# Confidential Information of ARM, Inc.
# Use subject to ARM license.
# Copyright (c) 2026 ARM, Inc.

# ACI Version r0p0-00eac0

# Reifier 3.1.1

VERSION 5.6 ;

BUSBITCHARS "[]" ;

#name: sram_sp_hdc_svt_rvt_hvt Compiler|TSMC cln65gplus 65nm Process, 0.525um2 Bitcell
#version: r0p0-00eac0
#comment: 
#configuration:  -instname "pingpong_sram_4096x16" -words 4096 -bits 16 -frequency 100 -mux 16 -pipeline off -write_mask off -wp_size 8 -write_thru on -top_layer "m5-m9" -power_type otc -redundancy off -rcols 2 -rrows 2 -bmux off -ser none -back_biasing off -power_gating off -retention on -ema on -atf off -cust_comment "" -bus_notation on -left_bus_delim "[" -right_bus_delim "]" -pwr_gnd_rename "VDDPE:VDDPE,VDDCE:VDDCE,VSSE:VSSE" -prefix "" -name_case upper -check_instname off -diodes on -drive 6 -dnw off -asvm on -corners ff_1p10v_1p10v_125c,tt_1p00v_1p00v_25c,ff_1p10v_1p10v_0c,ss_0p90v_0p90v_125c,ff_1p10v_1p10v_m40c,ss_0p90v_0p90v_m40c
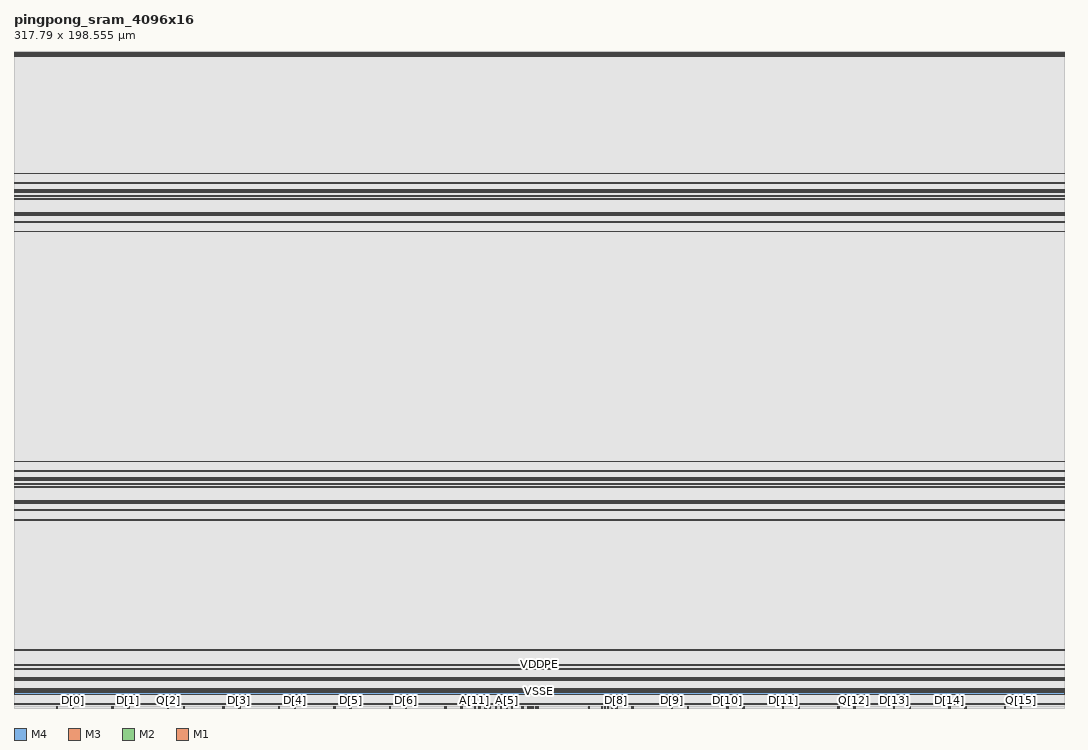
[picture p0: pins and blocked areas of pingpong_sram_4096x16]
MACRO pingpong_sram_4096x16
  FOREIGN pingpong_sram_4096x16 0 0 ;
  SYMMETRY X Y R90 ;
  SIZE 317.79 BY 198.555 ;
  CLASS BLOCK ;
  PIN A[2]
    DIRECTION INPUT ;
    USE SIGNAL ;
    SHAPE ABUTMENT ;
    PORT
      LAYER M4 ;
      RECT 155.545 0.0 155.885 0.34 ;
      LAYER M3 ;
      RECT 155.545 0.0 155.885 0.2 ;
      LAYER M2 ;
      RECT 155.545 0.0 155.885 0.2 ;
      LAYER M1 ;
      RECT 155.545 0.0 155.885 0.2 ;
      END
    ANTENNAGATEAREA 0.009 ;
    ANTENNADIFFAREA 0.1024 ;
    END A[2]
  PIN A[1]
    DIRECTION INPUT ;
    USE SIGNAL ;
    SHAPE ABUTMENT ;
    PORT
      LAYER M1 ;
      RECT 156.27 0.0 156.61 0.2 ;
      LAYER M2 ;
      RECT 156.27 0.0 156.61 0.2 ;
      LAYER M3 ;
      RECT 156.27 0.0 156.61 0.2 ;
      LAYER M4 ;
      RECT 156.27 0.0 156.61 0.34 ;
      END
    ANTENNAGATEAREA 0.009 ;
    ANTENNADIFFAREA 0.1024 ;
    END A[1]
  PIN A[3]
    DIRECTION INPUT ;
    USE SIGNAL ;
    SHAPE ABUTMENT ;
    PORT
      LAYER M4 ;
      RECT 153.72 0.0 154.06 0.34 ;
      LAYER M3 ;
      RECT 153.72 0.0 154.06 0.2 ;
      LAYER M2 ;
      RECT 153.72 0.0 154.06 0.2 ;
      LAYER M1 ;
      RECT 153.72 0.0 154.06 0.2 ;
      END
    ANTENNAGATEAREA 0.009 ;
    ANTENNADIFFAREA 0.1024 ;
    END A[3]
  PIN A[0]
    DIRECTION INPUT ;
    USE SIGNAL ;
    SHAPE ABUTMENT ;
    PORT
      LAYER M1 ;
      RECT 156.945 0.0 157.285 0.2 ;
      LAYER M2 ;
      RECT 156.945 0.0 157.285 0.2 ;
      LAYER M3 ;
      RECT 156.945 0.0 157.285 0.2 ;
      LAYER M4 ;
      RECT 156.945 0.0 157.285 0.34 ;
      END
    ANTENNAGATEAREA 0.009 ;
    ANTENNADIFFAREA 0.1024 ;
    END A[0]
  PIN A[4]
    DIRECTION INPUT ;
    USE SIGNAL ;
    SHAPE ABUTMENT ;
    PORT
      LAYER M4 ;
      RECT 150.47 0.0 150.81 0.34 ;
      LAYER M3 ;
      RECT 150.47 0.0 150.81 0.2 ;
      LAYER M2 ;
      RECT 150.47 0.0 150.81 0.2 ;
      LAYER M1 ;
      RECT 150.47 0.0 150.81 0.2 ;
      END
    ANTENNAGATEAREA 0.009 ;
    ANTENNADIFFAREA 0.1024 ;
    END A[4]
  PIN EMA[0]
    DIRECTION INPUT ;
    USE SIGNAL ;
    SHAPE ABUTMENT ;
    PORT
      LAYER M1 ;
      RECT 157.765 0.0 158.105 0.2 ;
      LAYER M2 ;
      RECT 157.765 0.0 158.105 0.2 ;
      LAYER M3 ;
      RECT 157.765 0.0 158.105 0.2 ;
      LAYER M4 ;
      RECT 157.765 0.0 158.105 0.34 ;
      END
    ANTENNAGATEAREA 0.009 ;
    ANTENNADIFFAREA 0.1024 ;
    END EMA[0]
  PIN A[5]
    DIRECTION INPUT ;
    USE SIGNAL ;
    SHAPE ABUTMENT ;
    PORT
      LAYER M4 ;
      RECT 149.05 0.0 149.39 0.34 ;
      LAYER M3 ;
      RECT 149.05 0.0 149.39 0.2 ;
      LAYER M2 ;
      RECT 149.05 0.0 149.39 0.2 ;
      LAYER M1 ;
      RECT 149.05 0.0 149.39 0.2 ;
      END
    ANTENNAGATEAREA 0.009 ;
    ANTENNADIFFAREA 0.1024 ;
    END A[5]
  PIN EMA[1]
    DIRECTION INPUT ;
    USE SIGNAL ;
    SHAPE ABUTMENT ;
    PORT
      LAYER M1 ;
      RECT 158.345 0.0 158.685 0.2 ;
      LAYER M2 ;
      RECT 158.345 0.0 158.685 0.2 ;
      LAYER M3 ;
      RECT 158.345 0.0 158.685 0.2 ;
      LAYER M4 ;
      RECT 158.345 0.0 158.685 0.34 ;
      END
    ANTENNAGATEAREA 0.009 ;
    ANTENNADIFFAREA 0.1024 ;
    END EMA[1]
  PIN A[6]
    DIRECTION INPUT ;
    USE SIGNAL ;
    SHAPE ABUTMENT ;
    PORT
      LAYER M4 ;
      RECT 147.22 0.0 147.56 0.34 ;
      LAYER M3 ;
      RECT 147.22 0.0 147.56 0.2 ;
      LAYER M2 ;
      RECT 147.22 0.0 147.56 0.2 ;
      LAYER M1 ;
      RECT 147.22 0.0 147.56 0.2 ;
      END
    ANTENNAGATEAREA 0.009 ;
    ANTENNADIFFAREA 0.1024 ;
    END A[6]
  PIN WEN
    DIRECTION INPUT ;
    USE SIGNAL ;
    SHAPE ABUTMENT ;
    PORT
      LAYER M1 ;
      RECT 173.735 0.0 174.075 0.2 ;
      LAYER M2 ;
      RECT 173.735 0.0 174.075 0.2 ;
      LAYER M3 ;
      RECT 173.735 0.0 174.075 0.2 ;
      LAYER M4 ;
      RECT 173.735 0.0 174.075 0.34 ;
      END
    ANTENNAGATEAREA 0.009 ;
    ANTENNADIFFAREA 0.1024 ;
    END WEN
  PIN A[7]
    DIRECTION INPUT ;
    USE SIGNAL ;
    SHAPE ABUTMENT ;
    PORT
      LAYER M4 ;
      RECT 145.8 0.0 146.14 0.34 ;
      LAYER M3 ;
      RECT 145.8 0.0 146.14 0.2 ;
      LAYER M2 ;
      RECT 145.8 0.0 146.14 0.2 ;
      LAYER M1 ;
      RECT 145.8 0.0 146.14 0.2 ;
      END
    ANTENNAGATEAREA 0.009 ;
    ANTENNADIFFAREA 0.1024 ;
    END A[7]
  PIN CEN
    DIRECTION INPUT ;
    USE SIGNAL ;
    SHAPE ABUTMENT ;
    PORT
      LAYER M1 ;
      RECT 177.82 0.0 178.16 0.2 ;
      LAYER M2 ;
      RECT 177.82 0.0 178.16 0.2 ;
      LAYER M3 ;
      RECT 177.82 0.0 178.16 0.2 ;
      LAYER M4 ;
      RECT 177.82 0.0 178.16 0.34 ;
      END
    ANTENNAGATEAREA 0.009 ;
    ANTENNADIFFAREA 0.1024 ;
    END CEN
  PIN A[8]
    DIRECTION INPUT ;
    USE SIGNAL ;
    SHAPE ABUTMENT ;
    PORT
      LAYER M4 ;
      RECT 143.97 0.0 144.31 0.34 ;
      LAYER M3 ;
      RECT 143.97 0.0 144.31 0.2 ;
      LAYER M2 ;
      RECT 143.97 0.0 144.31 0.2 ;
      LAYER M1 ;
      RECT 143.97 0.0 144.31 0.2 ;
      END
    ANTENNAGATEAREA 0.009 ;
    ANTENNADIFFAREA 0.1024 ;
    END A[8]
  PIN RETN
    DIRECTION INPUT ;
    USE SIGNAL ;
    SHAPE ABUTMENT ;
    PORT
      LAYER M1 ;
      RECT 178.625 0.0 178.965 0.2 ;
      LAYER M2 ;
      RECT 178.625 0.0 178.965 0.2 ;
      LAYER M3 ;
      RECT 178.625 0.0 178.965 0.2 ;
      LAYER M4 ;
      RECT 178.625 0.0 178.965 0.34 ;
      END
    ANTENNAGATEAREA 0.009 ;
    ANTENNADIFFAREA 0.1024 ;
    END RETN
  PIN A[9]
    DIRECTION INPUT ;
    USE SIGNAL ;
    SHAPE ABUTMENT ;
    PORT
      LAYER M4 ;
      RECT 142.55 0.0 142.89 0.34 ;
      LAYER M3 ;
      RECT 142.55 0.0 142.89 0.2 ;
      LAYER M2 ;
      RECT 142.55 0.0 142.89 0.2 ;
      LAYER M1 ;
      RECT 142.55 0.0 142.89 0.2 ;
      END
    ANTENNAGATEAREA 0.009 ;
    ANTENNADIFFAREA 0.1024 ;
    END A[9]
  PIN EMA[2]
    DIRECTION INPUT ;
    USE SIGNAL ;
    SHAPE ABUTMENT ;
    PORT
      LAYER M1 ;
      RECT 179.68 0.0 180.02 0.2 ;
      LAYER M2 ;
      RECT 179.68 0.0 180.02 0.2 ;
      LAYER M3 ;
      RECT 179.68 0.0 180.02 0.2 ;
      LAYER M4 ;
      RECT 179.68 0.0 180.02 0.34 ;
      END
    ANTENNAGATEAREA 0.009 ;
    ANTENNADIFFAREA 0.1024 ;
    END EMA[2]
  PIN A[10]
    DIRECTION INPUT ;
    USE SIGNAL ;
    SHAPE ABUTMENT ;
    PORT
      LAYER M4 ;
      RECT 140.72 0.0 141.06 0.34 ;
      LAYER M3 ;
      RECT 140.72 0.0 141.06 0.2 ;
      LAYER M2 ;
      RECT 140.72 0.0 141.06 0.2 ;
      LAYER M1 ;
      RECT 140.72 0.0 141.06 0.2 ;
      END
    ANTENNAGATEAREA 0.009 ;
    ANTENNADIFFAREA 0.1024 ;
    END A[10]
  PIN CLK
    DIRECTION INPUT ;
    USE SIGNAL ;
    SHAPE ABUTMENT ;
    PORT
      LAYER M1 ;
      RECT 180.69 0.0 181.03 0.2 ;
      LAYER M2 ;
      RECT 180.69 0.0 181.03 0.2 ;
      LAYER M3 ;
      RECT 180.69 0.0 181.03 0.2 ;
      LAYER M4 ;
      RECT 180.69 0.0 181.03 0.34 ;
      END
    ANTENNAGATEAREA 0.009 ;
    ANTENNADIFFAREA 0.1024 ;
    END CLK
  PIN A[11]
    DIRECTION INPUT ;
    USE SIGNAL ;
    SHAPE ABUTMENT ;
    PORT
      LAYER M4 ;
      RECT 139.3 0.0 139.64 0.34 ;
      LAYER M3 ;
      RECT 139.3 0.0 139.64 0.2 ;
      LAYER M2 ;
      RECT 139.3 0.0 139.64 0.2 ;
      LAYER M1 ;
      RECT 139.3 0.0 139.64 0.2 ;
      END
    ANTENNAGATEAREA 0.009 ;
    ANTENNADIFFAREA 0.1024 ;
    END A[11]
  PIN D[8]
    DIRECTION INPUT ;
    USE SIGNAL ;
    SHAPE ABUTMENT ;
    PORT
      LAYER M1 ;
      RECT 182.175 0.0 182.515 0.2 ;
      LAYER M2 ;
      RECT 182.175 0.0 182.515 0.2 ;
      LAYER M3 ;
      RECT 182.175 0.0 182.515 0.2 ;
      LAYER M4 ;
      RECT 182.175 0.0 182.515 0.34 ;
      END
    ANTENNAGATEAREA 0.009 ;
    ANTENNADIFFAREA 0.1024 ;
    END D[8]
  PIN D[7]
    DIRECTION INPUT ;
    USE SIGNAL ;
    SHAPE ABUTMENT ;
    PORT
      LAYER M4 ;
      RECT 135.275 0.0 135.615 0.34 ;
      LAYER M3 ;
      RECT 135.275 0.0 135.615 0.2 ;
      LAYER M2 ;
      RECT 135.275 0.0 135.615 0.2 ;
      LAYER M1 ;
      RECT 135.275 0.0 135.615 0.2 ;
      END
    ANTENNAGATEAREA 0.009 ;
    ANTENNADIFFAREA 0.1024 ;
    END D[7]
  PIN Q[8]
    DIRECTION OUTPUT ;
    USE SIGNAL ;
    SHAPE ABUTMENT ;
    PORT
      LAYER M1 ;
      RECT 187.005 0.0 187.345 0.2 ;
      LAYER M2 ;
      RECT 187.005 0.0 187.345 0.2 ;
      LAYER M3 ;
      RECT 187.005 0.0 187.345 0.2 ;
      LAYER M4 ;
      RECT 187.005 0.0 187.345 0.34 ;
      END
    ANTENNADIFFAREA 0.1024 ;
    END Q[8]
  PIN Q[7]
    DIRECTION OUTPUT ;
    USE SIGNAL ;
    SHAPE ABUTMENT ;
    PORT
      LAYER M4 ;
      RECT 130.445 0.0 130.785 0.34 ;
      LAYER M3 ;
      RECT 130.445 0.0 130.785 0.2 ;
      LAYER M2 ;
      RECT 130.445 0.0 130.785 0.2 ;
      LAYER M1 ;
      RECT 130.445 0.0 130.785 0.2 ;
      END
    ANTENNADIFFAREA 0.1024 ;
    END Q[7]
  PIN D[9]
    DIRECTION INPUT ;
    USE SIGNAL ;
    SHAPE ABUTMENT ;
    PORT
      LAYER M1 ;
      RECT 198.975 0.0 199.315 0.2 ;
      LAYER M2 ;
      RECT 198.975 0.0 199.315 0.2 ;
      LAYER M3 ;
      RECT 198.975 0.0 199.315 0.2 ;
      LAYER M4 ;
      RECT 198.975 0.0 199.315 0.34 ;
      END
    ANTENNAGATEAREA 0.009 ;
    ANTENNADIFFAREA 0.1024 ;
    END D[9]
  PIN D[6]
    DIRECTION INPUT ;
    USE SIGNAL ;
    SHAPE ABUTMENT ;
    PORT
      LAYER M4 ;
      RECT 118.475 0.0 118.815 0.34 ;
      LAYER M3 ;
      RECT 118.475 0.0 118.815 0.2 ;
      LAYER M2 ;
      RECT 118.475 0.0 118.815 0.2 ;
      LAYER M1 ;
      RECT 118.475 0.0 118.815 0.2 ;
      END
    ANTENNAGATEAREA 0.009 ;
    ANTENNADIFFAREA 0.1024 ;
    END D[6]
  PIN Q[9]
    DIRECTION OUTPUT ;
    USE SIGNAL ;
    SHAPE ABUTMENT ;
    PORT
      LAYER M1 ;
      RECT 203.805 0.0 204.145 0.2 ;
      LAYER M2 ;
      RECT 203.805 0.0 204.145 0.2 ;
      LAYER M3 ;
      RECT 203.805 0.0 204.145 0.2 ;
      LAYER M4 ;
      RECT 203.805 0.0 204.145 0.34 ;
      END
    ANTENNADIFFAREA 0.1024 ;
    END Q[9]
  PIN Q[6]
    DIRECTION OUTPUT ;
    USE SIGNAL ;
    SHAPE ABUTMENT ;
    PORT
      LAYER M4 ;
      RECT 113.645 0.0 113.985 0.34 ;
      LAYER M3 ;
      RECT 113.645 0.0 113.985 0.2 ;
      LAYER M2 ;
      RECT 113.645 0.0 113.985 0.2 ;
      LAYER M1 ;
      RECT 113.645 0.0 113.985 0.2 ;
      END
    ANTENNADIFFAREA 0.1024 ;
    END Q[6]
  PIN D[10]
    DIRECTION INPUT ;
    USE SIGNAL ;
    SHAPE ABUTMENT ;
    PORT
      LAYER M1 ;
      RECT 215.775 0.0 216.115 0.2 ;
      LAYER M2 ;
      RECT 215.775 0.0 216.115 0.2 ;
      LAYER M3 ;
      RECT 215.775 0.0 216.115 0.2 ;
      LAYER M4 ;
      RECT 215.775 0.0 216.115 0.34 ;
      END
    ANTENNAGATEAREA 0.009 ;
    ANTENNADIFFAREA 0.1024 ;
    END D[10]
  PIN D[5]
    DIRECTION INPUT ;
    USE SIGNAL ;
    SHAPE ABUTMENT ;
    PORT
      LAYER M4 ;
      RECT 101.675 0.0 102.015 0.34 ;
      LAYER M3 ;
      RECT 101.675 0.0 102.015 0.2 ;
      LAYER M2 ;
      RECT 101.675 0.0 102.015 0.2 ;
      LAYER M1 ;
      RECT 101.675 0.0 102.015 0.2 ;
      END
    ANTENNAGATEAREA 0.009 ;
    ANTENNADIFFAREA 0.1024 ;
    END D[5]
  PIN Q[10]
    DIRECTION OUTPUT ;
    USE SIGNAL ;
    SHAPE ABUTMENT ;
    PORT
      LAYER M1 ;
      RECT 220.605 0.0 220.945 0.2 ;
      LAYER M2 ;
      RECT 220.605 0.0 220.945 0.2 ;
      LAYER M3 ;
      RECT 220.605 0.0 220.945 0.2 ;
      LAYER M4 ;
      RECT 220.605 0.0 220.945 0.34 ;
      END
    ANTENNADIFFAREA 0.1024 ;
    END Q[10]
  PIN Q[5]
    DIRECTION OUTPUT ;
    USE SIGNAL ;
    SHAPE ABUTMENT ;
    PORT
      LAYER M4 ;
      RECT 96.845 0.0 97.185 0.34 ;
      LAYER M3 ;
      RECT 96.845 0.0 97.185 0.2 ;
      LAYER M2 ;
      RECT 96.845 0.0 97.185 0.2 ;
      LAYER M1 ;
      RECT 96.845 0.0 97.185 0.2 ;
      END
    ANTENNADIFFAREA 0.1024 ;
    END Q[5]
  PIN D[11]
    DIRECTION INPUT ;
    USE SIGNAL ;
    SHAPE ABUTMENT ;
    PORT
      LAYER M1 ;
      RECT 232.575 0.0 232.915 0.2 ;
      LAYER M2 ;
      RECT 232.575 0.0 232.915 0.2 ;
      LAYER M3 ;
      RECT 232.575 0.0 232.915 0.2 ;
      LAYER M4 ;
      RECT 232.575 0.0 232.915 0.34 ;
      END
    ANTENNAGATEAREA 0.009 ;
    ANTENNADIFFAREA 0.1024 ;
    END D[11]
  PIN D[4]
    DIRECTION INPUT ;
    USE SIGNAL ;
    SHAPE ABUTMENT ;
    PORT
      LAYER M4 ;
      RECT 84.875 0.0 85.215 0.34 ;
      LAYER M3 ;
      RECT 84.875 0.0 85.215 0.2 ;
      LAYER M2 ;
      RECT 84.875 0.0 85.215 0.2 ;
      LAYER M1 ;
      RECT 84.875 0.0 85.215 0.2 ;
      END
    ANTENNAGATEAREA 0.009 ;
    ANTENNADIFFAREA 0.1024 ;
    END D[4]
  PIN Q[11]
    DIRECTION OUTPUT ;
    USE SIGNAL ;
    SHAPE ABUTMENT ;
    PORT
      LAYER M1 ;
      RECT 237.405 0.0 237.745 0.2 ;
      LAYER M2 ;
      RECT 237.405 0.0 237.745 0.2 ;
      LAYER M3 ;
      RECT 237.405 0.0 237.745 0.2 ;
      LAYER M4 ;
      RECT 237.405 0.0 237.745 0.34 ;
      END
    ANTENNADIFFAREA 0.1024 ;
    END Q[11]
  PIN Q[4]
    DIRECTION OUTPUT ;
    USE SIGNAL ;
    SHAPE ABUTMENT ;
    PORT
      LAYER M4 ;
      RECT 80.045 0.0 80.385 0.34 ;
      LAYER M3 ;
      RECT 80.045 0.0 80.385 0.2 ;
      LAYER M2 ;
      RECT 80.045 0.0 80.385 0.2 ;
      LAYER M1 ;
      RECT 80.045 0.0 80.385 0.2 ;
      END
    ANTENNADIFFAREA 0.1024 ;
    END Q[4]
  PIN D[12]
    DIRECTION INPUT ;
    USE SIGNAL ;
    SHAPE ABUTMENT ;
    PORT
      LAYER M1 ;
      RECT 249.375 0.0 249.715 0.2 ;
      LAYER M2 ;
      RECT 249.375 0.0 249.715 0.2 ;
      LAYER M3 ;
      RECT 249.375 0.0 249.715 0.2 ;
      LAYER M4 ;
      RECT 249.375 0.0 249.715 0.34 ;
      END
    ANTENNAGATEAREA 0.009 ;
    ANTENNADIFFAREA 0.1024 ;
    END D[12]
  PIN D[3]
    DIRECTION INPUT ;
    USE SIGNAL ;
    SHAPE ABUTMENT ;
    PORT
      LAYER M4 ;
      RECT 68.075 0.0 68.415 0.34 ;
      LAYER M3 ;
      RECT 68.075 0.0 68.415 0.2 ;
      LAYER M2 ;
      RECT 68.075 0.0 68.415 0.2 ;
      LAYER M1 ;
      RECT 68.075 0.0 68.415 0.2 ;
      END
    ANTENNAGATEAREA 0.009 ;
    ANTENNADIFFAREA 0.1024 ;
    END D[3]
  PIN Q[12]
    DIRECTION OUTPUT ;
    USE SIGNAL ;
    SHAPE ABUTMENT ;
    PORT
      LAYER M1 ;
      RECT 254.205 0.0 254.545 0.2 ;
      LAYER M2 ;
      RECT 254.205 0.0 254.545 0.2 ;
      LAYER M3 ;
      RECT 254.205 0.0 254.545 0.2 ;
      LAYER M4 ;
      RECT 254.205 0.0 254.545 0.34 ;
      END
    ANTENNADIFFAREA 0.1024 ;
    END Q[12]
  PIN Q[3]
    DIRECTION OUTPUT ;
    USE SIGNAL ;
    SHAPE ABUTMENT ;
    PORT
      LAYER M4 ;
      RECT 63.245 0.0 63.585 0.34 ;
      LAYER M3 ;
      RECT 63.245 0.0 63.585 0.2 ;
      LAYER M2 ;
      RECT 63.245 0.0 63.585 0.2 ;
      LAYER M1 ;
      RECT 63.245 0.0 63.585 0.2 ;
      END
    ANTENNADIFFAREA 0.1024 ;
    END Q[3]
  PIN D[13]
    DIRECTION INPUT ;
    USE SIGNAL ;
    SHAPE ABUTMENT ;
    PORT
      LAYER M1 ;
      RECT 266.175 0.0 266.515 0.2 ;
      LAYER M2 ;
      RECT 266.175 0.0 266.515 0.2 ;
      LAYER M3 ;
      RECT 266.175 0.0 266.515 0.2 ;
      LAYER M4 ;
      RECT 266.175 0.0 266.515 0.34 ;
      END
    ANTENNAGATEAREA 0.009 ;
    ANTENNADIFFAREA 0.1024 ;
    END D[13]
  PIN D[2]
    DIRECTION INPUT ;
    USE SIGNAL ;
    SHAPE ABUTMENT ;
    PORT
      LAYER M4 ;
      RECT 51.275 0.0 51.615 0.34 ;
      LAYER M3 ;
      RECT 51.275 0.0 51.615 0.2 ;
      LAYER M2 ;
      RECT 51.275 0.0 51.615 0.2 ;
      LAYER M1 ;
      RECT 51.275 0.0 51.615 0.2 ;
      END
    ANTENNAGATEAREA 0.009 ;
    ANTENNADIFFAREA 0.1024 ;
    END D[2]
  PIN Q[13]
    DIRECTION OUTPUT ;
    USE SIGNAL ;
    SHAPE ABUTMENT ;
    PORT
      LAYER M1 ;
      RECT 271.005 0.0 271.345 0.2 ;
      LAYER M2 ;
      RECT 271.005 0.0 271.345 0.2 ;
      LAYER M3 ;
      RECT 271.005 0.0 271.345 0.2 ;
      LAYER M4 ;
      RECT 271.005 0.0 271.345 0.34 ;
      END
    ANTENNADIFFAREA 0.1024 ;
    END Q[13]
  PIN Q[2]
    DIRECTION OUTPUT ;
    USE SIGNAL ;
    SHAPE ABUTMENT ;
    PORT
      LAYER M4 ;
      RECT 46.445 0.0 46.785 0.34 ;
      LAYER M3 ;
      RECT 46.445 0.0 46.785 0.2 ;
      LAYER M2 ;
      RECT 46.445 0.0 46.785 0.2 ;
      LAYER M1 ;
      RECT 46.445 0.0 46.785 0.2 ;
      END
    ANTENNADIFFAREA 0.1024 ;
    END Q[2]
  PIN D[14]
    DIRECTION INPUT ;
    USE SIGNAL ;
    SHAPE ABUTMENT ;
    PORT
      LAYER M1 ;
      RECT 282.975 0.0 283.315 0.2 ;
      LAYER M2 ;
      RECT 282.975 0.0 283.315 0.2 ;
      LAYER M3 ;
      RECT 282.975 0.0 283.315 0.2 ;
      LAYER M4 ;
      RECT 282.975 0.0 283.315 0.34 ;
      END
    ANTENNAGATEAREA 0.009 ;
    ANTENNADIFFAREA 0.1024 ;
    END D[14]
  PIN D[1]
    DIRECTION INPUT ;
    USE SIGNAL ;
    SHAPE ABUTMENT ;
    PORT
      LAYER M4 ;
      RECT 34.475 0.0 34.815 0.34 ;
      LAYER M3 ;
      RECT 34.475 0.0 34.815 0.2 ;
      LAYER M2 ;
      RECT 34.475 0.0 34.815 0.2 ;
      LAYER M1 ;
      RECT 34.475 0.0 34.815 0.2 ;
      END
    ANTENNAGATEAREA 0.009 ;
    ANTENNADIFFAREA 0.1024 ;
    END D[1]
  PIN Q[14]
    DIRECTION OUTPUT ;
    USE SIGNAL ;
    SHAPE ABUTMENT ;
    PORT
      LAYER M1 ;
      RECT 287.805 0.0 288.145 0.2 ;
      LAYER M2 ;
      RECT 287.805 0.0 288.145 0.2 ;
      LAYER M3 ;
      RECT 287.805 0.0 288.145 0.2 ;
      LAYER M4 ;
      RECT 287.805 0.0 288.145 0.34 ;
      END
    ANTENNADIFFAREA 0.1024 ;
    END Q[14]
  PIN Q[1]
    DIRECTION OUTPUT ;
    USE SIGNAL ;
    SHAPE ABUTMENT ;
    PORT
      LAYER M4 ;
      RECT 29.645 0.0 29.985 0.34 ;
      LAYER M3 ;
      RECT 29.645 0.0 29.985 0.2 ;
      LAYER M2 ;
      RECT 29.645 0.0 29.985 0.2 ;
      LAYER M1 ;
      RECT 29.645 0.0 29.985 0.2 ;
      END
    ANTENNADIFFAREA 0.1024 ;
    END Q[1]
  PIN D[15]
    DIRECTION INPUT ;
    USE SIGNAL ;
    SHAPE ABUTMENT ;
    PORT
      LAYER M1 ;
      RECT 299.775 0.0 300.115 0.2 ;
      LAYER M2 ;
      RECT 299.775 0.0 300.115 0.2 ;
      LAYER M3 ;
      RECT 299.775 0.0 300.115 0.2 ;
      LAYER M4 ;
      RECT 299.775 0.0 300.115 0.34 ;
      END
    ANTENNAGATEAREA 0.009 ;
    ANTENNADIFFAREA 0.1024 ;
    END D[15]
  PIN D[0]
    DIRECTION INPUT ;
    USE SIGNAL ;
    SHAPE ABUTMENT ;
    PORT
      LAYER M4 ;
      RECT 17.675 0.0 18.015 0.34 ;
      LAYER M3 ;
      RECT 17.675 0.0 18.015 0.2 ;
      LAYER M2 ;
      RECT 17.675 0.0 18.015 0.2 ;
      LAYER M1 ;
      RECT 17.675 0.0 18.015 0.2 ;
      END
    ANTENNAGATEAREA 0.009 ;
    ANTENNADIFFAREA 0.1024 ;
    END D[0]
  PIN Q[15]
    DIRECTION OUTPUT ;
    USE SIGNAL ;
    SHAPE ABUTMENT ;
    PORT
      LAYER M1 ;
      RECT 304.605 0.0 304.945 0.2 ;
      LAYER M2 ;
      RECT 304.605 0.0 304.945 0.2 ;
      LAYER M3 ;
      RECT 304.605 0.0 304.945 0.2 ;
      LAYER M4 ;
      RECT 304.605 0.0 304.945 0.34 ;
      END
    ANTENNADIFFAREA 0.1024 ;
    END Q[15]
  PIN Q[0]
    DIRECTION OUTPUT ;
    USE SIGNAL ;
    SHAPE ABUTMENT ;
    PORT
      LAYER M4 ;
      RECT 12.845 0.0 13.185 0.34 ;
      LAYER M3 ;
      RECT 12.845 0.0 13.185 0.2 ;
      LAYER M2 ;
      RECT 12.845 0.0 13.185 0.2 ;
      LAYER M1 ;
      RECT 12.845 0.0 13.185 0.2 ;
      END
    ANTENNADIFFAREA 0.1024 ;
    END Q[0]
  PIN VDDPE
    DIRECTION INOUT ;
    USE POWER ;
    PORT
      LAYER M4 ;
      RECT 0.0 5.59 317.79 6.01 ;
      END
    PORT
      LAYER M4 ;
      RECT 0.0 8.95 317.79 9.37 ;
      END
    PORT
      LAYER M4 ;
      RECT 0.0 12.78 317.79 13.28 ;
      END
    PORT
      LAYER M4 ;
      RECT 0.0 59.75 317.79 59.95 ;
      END
    PORT
      LAYER M4 ;
      RECT 0.0 62.63 317.79 62.85 ;
      END
    PORT
      LAYER M4 ;
      RECT 0.0 66.595 317.79 66.895 ;
      END
    PORT
      LAYER M4 ;
      RECT 0.0 68.755 317.79 68.975 ;
      END
    PORT
      LAYER M4 ;
      RECT 0.0 71.655 317.79 71.855 ;
      END
    PORT
      LAYER M4 ;
      RECT 0.0 146.955 317.79 147.155 ;
      END
    PORT
      LAYER M4 ;
      RECT 0.0 149.835 317.79 150.055 ;
      END
    PORT
      LAYER M4 ;
      RECT 0.0 153.8 317.79 154.1 ;
      END
    PORT
      LAYER M4 ;
      RECT 0.0 155.96 317.79 156.18 ;
      END
    PORT
      LAYER M4 ;
      RECT 0.0 158.86 317.79 159.06 ;
      END
    PORT
      LAYER M4 ;
      RECT 0.0 198.015 317.79 198.315 ;
      END
    END VDDPE
  PIN VDDCE
    DIRECTION INOUT ;
    USE POWER ;
    PORT
      LAYER M4 ;
      RECT 0.0 4.19 317.79 4.61 ;
      END
    PORT
      LAYER M4 ;
      RECT 0.0 17.455 317.79 17.825 ;
      END
    PORT
      LAYER M4 ;
      RECT 0.0 61.83 317.79 62.03 ;
      END
    PORT
      LAYER M4 ;
      RECT 0.0 69.575 317.79 69.775 ;
      END
    PORT
      LAYER M4 ;
      RECT 0.0 149.035 317.79 149.235 ;
      END
    PORT
      LAYER M4 ;
      RECT 0.0 156.78 317.79 156.98 ;
      END
    PORT
      LAYER M4 ;
      RECT 0.0 197.215 317.79 197.415 ;
      END
    END VDDCE
  PIN VSSE
    DIRECTION INOUT ;
    USE GROUND ;
    PORT
      LAYER M4 ;
      RECT 0.0 1.15 317.79 1.45 ;
      END
    PORT
      LAYER M4 ;
      RECT 0.0 4.89 317.79 5.31 ;
      END
    PORT
      LAYER M4 ;
      RECT 0.0 8.25 317.79 8.67 ;
      END
    PORT
      LAYER M4 ;
      RECT 0.0 11.67 317.79 12.09 ;
      END
    PORT
      LAYER M4 ;
      RECT 0.0 56.895 317.79 57.095 ;
      END
    PORT
      LAYER M4 ;
      RECT 0.0 62.23 317.79 62.43 ;
      END
    PORT
      LAYER M4 ;
      RECT 0.0 67.695 317.79 67.895 ;
      END
    PORT
      LAYER M4 ;
      RECT 0.0 69.175 317.79 69.375 ;
      END
    PORT
      LAYER M4 ;
      RECT 0.0 74.51 317.79 74.71 ;
      END
    PORT
      LAYER M4 ;
      RECT 0.0 144.1 317.79 144.3 ;
      END
    PORT
      LAYER M4 ;
      RECT 0.0 149.435 317.79 149.635 ;
      END
    PORT
      LAYER M4 ;
      RECT 0.0 154.9 317.79 155.1 ;
      END
    PORT
      LAYER M4 ;
      RECT 0.0 156.38 317.79 156.58 ;
      END
    PORT
      LAYER M4 ;
      RECT 0.0 161.715 317.79 161.915 ;
      END
    PORT
      LAYER M4 ;
      RECT 0.0 197.615 317.79 197.815 ;
      END
    END VSSE
  OBS
    #otc obstructions
    LAYER M1 DESIGNRULEWIDTH 0.1 ;
    RECT 305.045 0.0 317.79 0.3 ;
    RECT 300.215 0.0 304.505 0.3 ;
    RECT 288.245 0.0 299.675 0.3 ;
    RECT 283.415 0.0 287.705 0.3 ;
    RECT 271.445 0.0 282.875 0.3 ;
    RECT 266.615 0.0 270.905 0.3 ;
    RECT 254.645 0.0 266.075 0.3 ;
    RECT 249.815 0.0 254.105 0.3 ;
    RECT 237.845 0.0 249.275 0.3 ;
    RECT 233.015 0.0 237.305 0.3 ;
    RECT 221.045 0.0 232.475 0.3 ;
    RECT 216.215 0.0 220.505 0.3 ;
    RECT 204.245 0.0 215.675 0.3 ;
    RECT 199.415 0.0 203.705 0.3 ;
    RECT 187.445 0.0 198.875 0.3 ;
    RECT 182.615 0.0 186.905 0.3 ;
    RECT 181.13 0.0 182.075 0.3 ;
    RECT 180.12 0.0 180.59 0.3 ;
    RECT 179.065 0.0 179.58 0.3 ;
    RECT 178.26 0.0 178.525 0.3 ;
    RECT 174.175 0.0 177.72 0.3 ;
    RECT 158.785 0.0 173.635 0.3 ;
    RECT 157.385 0.0 157.665 0.3 ;
    RECT 156.71 0.0 156.845 0.3 ;
    RECT 155.985 0.0 156.17 0.3 ;
    RECT 154.16 0.0 155.445 0.3 ;
    RECT 150.91 0.0 153.62 0.3 ;
    RECT 149.49 0.0 150.37 0.3 ;
    RECT 147.66 0.0 148.95 0.3 ;
    RECT 146.24 0.0 147.12 0.3 ;
    RECT 144.41 0.0 145.7 0.3 ;
    RECT 142.99 0.0 143.87 0.3 ;
    RECT 141.16 0.0 142.45 0.3 ;
    RECT 139.74 0.0 140.62 0.3 ;
    RECT 135.715 0.0 139.2 0.3 ;
    RECT 130.885 0.0 135.175 0.3 ;
    RECT 118.915 0.0 130.345 0.3 ;
    RECT 114.085 0.0 118.375 0.3 ;
    RECT 102.115 0.0 113.545 0.3 ;
    RECT 97.285 0.0 101.575 0.3 ;
    RECT 85.315 0.0 96.745 0.3 ;
    RECT 80.485 0.0 84.775 0.3 ;
    RECT 68.515 0.0 79.945 0.3 ;
    RECT 63.685 0.0 67.975 0.3 ;
    RECT 51.715 0.0 63.145 0.3 ;
    RECT 46.885 0.0 51.175 0.3 ;
    RECT 34.915 0.0 46.345 0.3 ;
    RECT 30.085 0.0 34.375 0.3 ;
    RECT 18.115 0.0 29.545 0.3 ;
    RECT 13.285 0.0 17.575 0.3 ;
    RECT 0.0 0.0 12.745 0.3 ;
    RECT 0.0 0.3 317.79 198.555 ;
    LAYER VIA1 ;
    RECT 0.0 0.0 317.79 198.555 ;
    LAYER M2 DESIGNRULEWIDTH 0.1 ;
    RECT 305.045 0.0 317.79 0.3 ;
    RECT 300.215 0.0 304.505 0.3 ;
    RECT 288.245 0.0 299.675 0.3 ;
    RECT 283.415 0.0 287.705 0.3 ;
    RECT 271.445 0.0 282.875 0.3 ;
    RECT 266.615 0.0 270.905 0.3 ;
    RECT 254.645 0.0 266.075 0.3 ;
    RECT 249.815 0.0 254.105 0.3 ;
    RECT 237.845 0.0 249.275 0.3 ;
    RECT 233.015 0.0 237.305 0.3 ;
    RECT 221.045 0.0 232.475 0.3 ;
    RECT 216.215 0.0 220.505 0.3 ;
    RECT 204.245 0.0 215.675 0.3 ;
    RECT 199.415 0.0 203.705 0.3 ;
    RECT 187.445 0.0 198.875 0.3 ;
    RECT 182.615 0.0 186.905 0.3 ;
    RECT 181.13 0.0 182.075 0.3 ;
    RECT 180.12 0.0 180.59 0.3 ;
    RECT 179.065 0.0 179.58 0.3 ;
    RECT 178.26 0.0 178.525 0.3 ;
    RECT 174.175 0.0 177.72 0.3 ;
    RECT 158.785 0.0 173.635 0.3 ;
    RECT 157.385 0.0 157.665 0.3 ;
    RECT 156.71 0.0 156.845 0.3 ;
    RECT 155.985 0.0 156.17 0.3 ;
    RECT 154.16 0.0 155.445 0.3 ;
    RECT 150.91 0.0 153.62 0.3 ;
    RECT 149.49 0.0 150.37 0.3 ;
    RECT 147.66 0.0 148.95 0.3 ;
    RECT 146.24 0.0 147.12 0.3 ;
    RECT 144.41 0.0 145.7 0.3 ;
    RECT 142.99 0.0 143.87 0.3 ;
    RECT 141.16 0.0 142.45 0.3 ;
    RECT 139.74 0.0 140.62 0.3 ;
    RECT 135.715 0.0 139.2 0.3 ;
    RECT 130.885 0.0 135.175 0.3 ;
    RECT 118.915 0.0 130.345 0.3 ;
    RECT 114.085 0.0 118.375 0.3 ;
    RECT 102.115 0.0 113.545 0.3 ;
    RECT 97.285 0.0 101.575 0.3 ;
    RECT 85.315 0.0 96.745 0.3 ;
    RECT 80.485 0.0 84.775 0.3 ;
    RECT 68.515 0.0 79.945 0.3 ;
    RECT 63.685 0.0 67.975 0.3 ;
    RECT 51.715 0.0 63.145 0.3 ;
    RECT 46.885 0.0 51.175 0.3 ;
    RECT 34.915 0.0 46.345 0.3 ;
    RECT 30.085 0.0 34.375 0.3 ;
    RECT 18.115 0.0 29.545 0.3 ;
    RECT 13.285 0.0 17.575 0.3 ;
    RECT 0.0 0.0 12.745 0.3 ;
    RECT 0.0 0.3 317.79 198.555 ;
    LAYER VIA2 ;
    RECT 0.0 0.0 317.79 198.555 ;
    LAYER M3 DESIGNRULEWIDTH 0.1 ;
    RECT 305.045 0.0 317.79 0.3 ;
    RECT 300.215 0.0 304.505 0.3 ;
    RECT 288.245 0.0 299.675 0.3 ;
    RECT 283.415 0.0 287.705 0.3 ;
    RECT 271.445 0.0 282.875 0.3 ;
    RECT 266.615 0.0 270.905 0.3 ;
    RECT 254.645 0.0 266.075 0.3 ;
    RECT 249.815 0.0 254.105 0.3 ;
    RECT 237.845 0.0 249.275 0.3 ;
    RECT 233.015 0.0 237.305 0.3 ;
    RECT 221.045 0.0 232.475 0.3 ;
    RECT 216.215 0.0 220.505 0.3 ;
    RECT 204.245 0.0 215.675 0.3 ;
    RECT 199.415 0.0 203.705 0.3 ;
    RECT 187.445 0.0 198.875 0.3 ;
    RECT 182.615 0.0 186.905 0.3 ;
    RECT 181.13 0.0 182.075 0.3 ;
    RECT 180.12 0.0 180.59 0.3 ;
    RECT 179.065 0.0 179.58 0.3 ;
    RECT 178.26 0.0 178.525 0.3 ;
    RECT 174.175 0.0 177.72 0.3 ;
    RECT 158.785 0.0 173.635 0.3 ;
    RECT 157.385 0.0 157.665 0.3 ;
    RECT 156.71 0.0 156.845 0.3 ;
    RECT 155.985 0.0 156.17 0.3 ;
    RECT 154.16 0.0 155.445 0.3 ;
    RECT 150.91 0.0 153.62 0.3 ;
    RECT 149.49 0.0 150.37 0.3 ;
    RECT 147.66 0.0 148.95 0.3 ;
    RECT 146.24 0.0 147.12 0.3 ;
    RECT 144.41 0.0 145.7 0.3 ;
    RECT 142.99 0.0 143.87 0.3 ;
    RECT 141.16 0.0 142.45 0.3 ;
    RECT 139.74 0.0 140.62 0.3 ;
    RECT 135.715 0.0 139.2 0.3 ;
    RECT 130.885 0.0 135.175 0.3 ;
    RECT 118.915 0.0 130.345 0.3 ;
    RECT 114.085 0.0 118.375 0.3 ;
    RECT 102.115 0.0 113.545 0.3 ;
    RECT 97.285 0.0 101.575 0.3 ;
    RECT 85.315 0.0 96.745 0.3 ;
    RECT 80.485 0.0 84.775 0.3 ;
    RECT 68.515 0.0 79.945 0.3 ;
    RECT 63.685 0.0 67.975 0.3 ;
    RECT 51.715 0.0 63.145 0.3 ;
    RECT 46.885 0.0 51.175 0.3 ;
    RECT 34.915 0.0 46.345 0.3 ;
    RECT 30.085 0.0 34.375 0.3 ;
    RECT 18.115 0.0 29.545 0.3 ;
    RECT 13.285 0.0 17.575 0.3 ;
    RECT 0.0 0.0 12.745 0.3 ;
    RECT 0.0 0.3 317.79 198.555 ;
    LAYER VIA3 ;
    RECT 0.0 0.0 317.79 198.555 ;
    LAYER M4 DESIGNRULEWIDTH 0.1 ;
    RECT 305.045 0.0 317.79 0.44 ;
    RECT 300.215 0.0 304.505 0.44 ;
    RECT 288.245 0.0 299.675 0.44 ;
    RECT 283.415 0.0 287.705 0.44 ;
    RECT 271.445 0.0 282.875 0.44 ;
    RECT 266.615 0.0 270.905 0.44 ;
    RECT 254.645 0.0 266.075 0.44 ;
    RECT 249.815 0.0 254.105 0.44 ;
    RECT 237.845 0.0 249.275 0.44 ;
    RECT 233.015 0.0 237.305 0.44 ;
    RECT 221.045 0.0 232.475 0.44 ;
    RECT 216.215 0.0 220.505 0.44 ;
    RECT 204.245 0.0 215.675 0.44 ;
    RECT 199.415 0.0 203.705 0.44 ;
    RECT 187.445 0.0 198.875 0.44 ;
    RECT 182.615 0.0 186.905 0.44 ;
    RECT 181.13 0.0 182.075 0.44 ;
    RECT 180.12 0.0 180.59 0.44 ;
    RECT 179.065 0.0 179.58 0.44 ;
    RECT 178.26 0.0 178.525 0.44 ;
    RECT 174.175 0.0 177.72 0.44 ;
    RECT 158.785 0.0 173.635 0.44 ;
    RECT 157.385 0.0 157.665 0.44 ;
    RECT 156.71 0.0 156.845 0.44 ;
    RECT 155.985 0.0 156.17 0.44 ;
    RECT 154.16 0.0 155.445 0.44 ;
    RECT 150.91 0.0 153.62 0.44 ;
    RECT 149.49 0.0 150.37 0.44 ;
    RECT 147.66 0.0 148.95 0.44 ;
    RECT 146.24 0.0 147.12 0.44 ;
    RECT 144.41 0.0 145.7 0.44 ;
    RECT 142.99 0.0 143.87 0.44 ;
    RECT 141.16 0.0 142.45 0.44 ;
    RECT 139.74 0.0 140.62 0.44 ;
    RECT 135.715 0.0 139.2 0.44 ;
    RECT 130.885 0.0 135.175 0.44 ;
    RECT 118.915 0.0 130.345 0.44 ;
    RECT 114.085 0.0 118.375 0.44 ;
    RECT 102.115 0.0 113.545 0.44 ;
    RECT 97.285 0.0 101.575 0.44 ;
    RECT 85.315 0.0 96.745 0.44 ;
    RECT 80.485 0.0 84.775 0.44 ;
    RECT 68.515 0.0 79.945 0.44 ;
    RECT 63.685 0.0 67.975 0.44 ;
    RECT 51.715 0.0 63.145 0.44 ;
    RECT 46.885 0.0 51.175 0.44 ;
    RECT 34.915 0.0 46.345 0.44 ;
    RECT 30.085 0.0 34.375 0.44 ;
    RECT 18.115 0.0 29.545 0.44 ;
    RECT 13.285 0.0 17.575 0.44 ;
    RECT 0.0 0.0 12.745 0.44 ;
    RECT 0.0 0.44 317.79 1.15 ;
    RECT 0.0 1.45 317.79 4.19 ;
    RECT 0.0 4.61 317.79 4.89 ;
    RECT 0.0 5.31 317.79 5.59 ;
    RECT 0.0 6.01 317.79 8.25 ;
    RECT 0.0 8.67 317.79 8.95 ;
    RECT 0.0 9.37 317.79 11.67 ;
    RECT 0.0 12.09 317.79 12.78 ;
    RECT 0.0 13.28 317.79 17.455 ;
    RECT 0.0 17.825 317.79 56.895 ;
    RECT 0.0 57.095 317.79 59.75 ;
    RECT 0.0 59.95 317.79 61.83 ;
    RECT 0.0 62.03 317.79 62.23 ;
    RECT 0.0 62.43 317.79 62.63 ;
    RECT 0.0 62.85 317.79 66.595 ;
    RECT 0.0 66.895 317.79 67.695 ;
    RECT 0.0 67.895 317.79 68.755 ;
    RECT 0.0 68.975 317.79 69.175 ;
    RECT 0.0 69.375 317.79 69.575 ;
    RECT 0.0 69.775 317.79 71.655 ;
    RECT 0.0 71.855 317.79 74.51 ;
    RECT 0.0 74.71 317.79 144.1 ;
    RECT 0.0 144.3 317.79 146.955 ;
    RECT 0.0 147.155 317.79 149.035 ;
    RECT 0.0 149.235 317.79 149.435 ;
    RECT 0.0 149.635 317.79 149.835 ;
    RECT 0.0 150.055 317.79 153.8 ;
    RECT 0.0 154.1 317.79 154.9 ;
    RECT 0.0 155.1 317.79 155.96 ;
    RECT 0.0 156.18 317.79 156.38 ;
    RECT 0.0 156.58 317.79 156.78 ;
    RECT 0.0 156.98 317.79 158.86 ;
    RECT 0.0 159.06 317.79 161.715 ;
    RECT 0.0 161.915 317.79 197.215 ;
    RECT 0.0 197.415 317.79 197.615 ;
    RECT 0.0 197.815 317.79 198.015 ;
    RECT 0.0 198.315 317.79 198.555 ;
    END
  END pingpong_sram_4096x16

END LIBRARY

